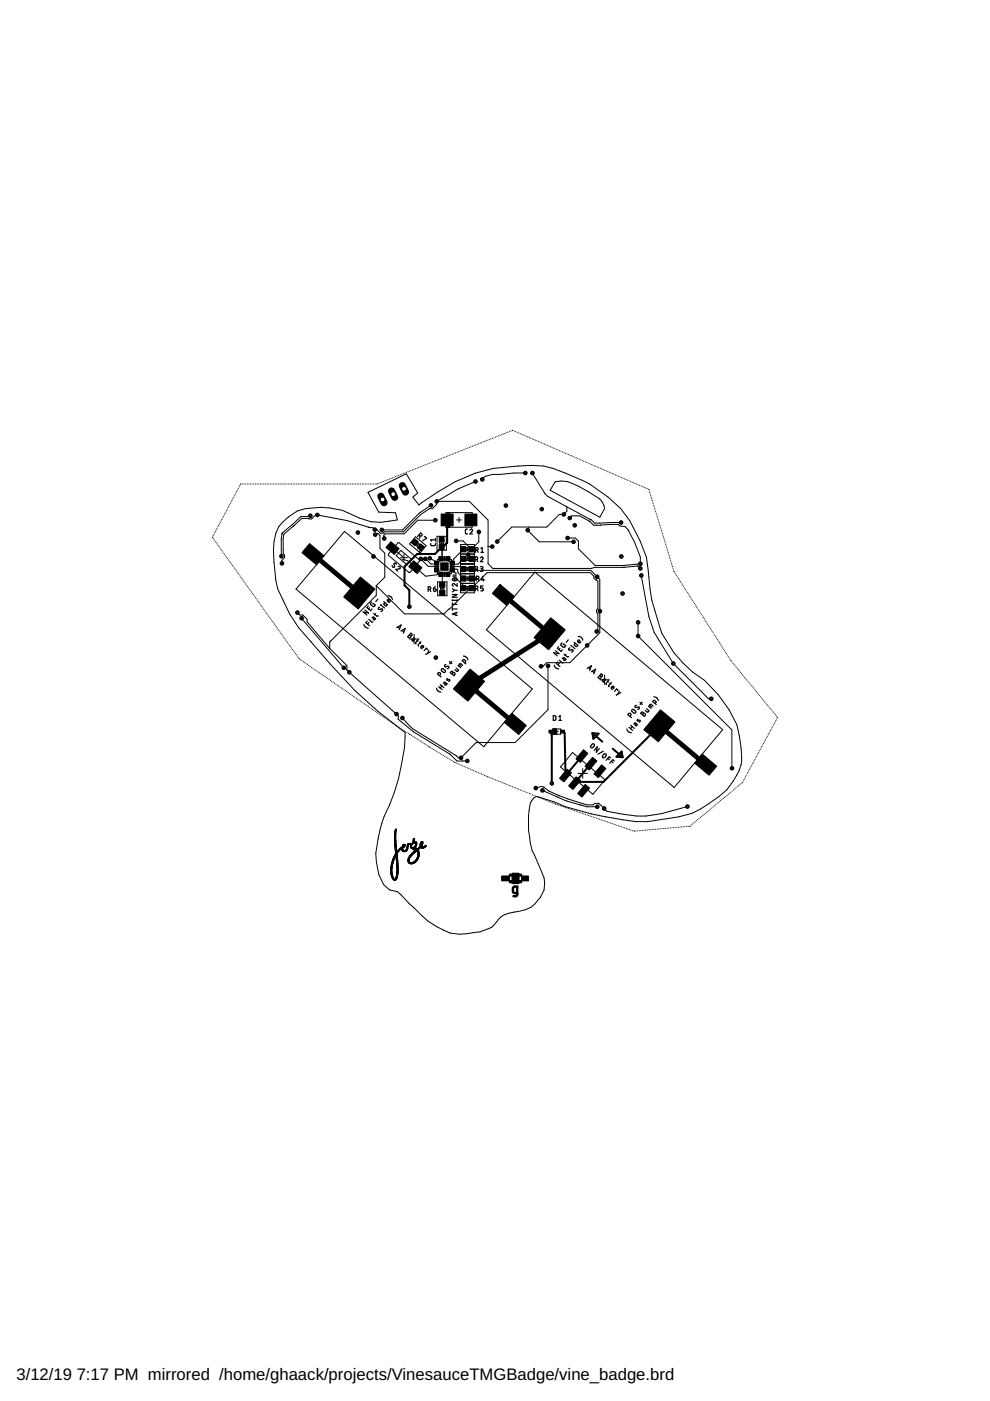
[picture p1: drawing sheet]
<svg xmlns="http://www.w3.org/2000/svg" width="210mm" height="297mm" viewBox="0 0 210 297" stroke-linecap="round" stroke-linejoin="round" font-family="sans-serif">
<defs><g id="words">
<g font-size="3.5">
<text x="3.5" y="292.5">3/12/19</text>
<text x="16.3" y="292.5">7:17 PM mirrored /home/ghaack/projects/VinesauceTMGBadge/vine_badge.brd</text>
</g>
</g></defs>
<g fill="#000" stroke="#000" stroke-width=".21">
<path d="M65.6 115.3l3.1 2.5-1.6 1.9-3.1-2.5zM82.9 114.9l1.7 1.4-1 1.3-1.8-1.5zM87.9 114.2l.8 .7-.7 .8-.8-.6zM89.2 115.3l.8 .7-.7 .8-.8-.6zM92.1 119.5h.9v.3h-.9zM92.1 120h.9v.3h-.9zM93.6 118h.3v.9h-.3zM93.1 115.5h1v1.1h-1zM93.1 113.8h1v1.1h-1zM94.1 118h.3v.9h-.3zM94.6 118h.3v.9h-.3zM93.5 119.3h1.5v1.6h-1.5z"/>
<path d="M93.5 109h2.6v2.5h-2.6zM95.4 120h1v.3h-1zM95.4 119.5h1v.3h-1zM97.7 115.9h1.1v1.1h-1.1zM97.7 117.9h1.1v1.1h-1.1zM99.4 115.9h1.1v1.1h-1.1zM99.4 117.9h1.1v1.1h-1.1zM98.6 109h2.5v2.5h-2.5zM76.4 122.3l3.1 2.6-3.6 4.2-3-2.5zM87.7 118.9l1.8 1.5-1.1 1.2-1.7-1.5zM92.1 120.5h.9v.3h-.9zM93.6 121.3h.3v.9h-.3z"/>
<path d="M93.2 123.5h1.1v1h-1.1zM93.2 125.2h1.1v1h-1.1zM94.1 121.3h.3v.9h-.3zM94.6 121.3h.3v.9h-.3zM95.4 120.5h1v.3h-1zM97.7 120.1h1.1v1.1h-1.1zM97.7 122.1h1.1v1.1h-1.1zM97.7 124.1h1.1v1.1h-1.1zM99.4 120.1h1.1v1.1h-1.1zM99.4 122.1h1.1v1.1h-1.1zM99.4 124.1h1.1v1.1h-1.1zM106 123.9l3.1 2.6-1.6 1.9-3.1-2.6z"/>
<path d="M116.8 131l3 2.5-3.5 4.3-3.1-2.6zM99.7 141.9l3 2.5-3.5 4.3-3.1-2.6zM108.5 151.2l3.1 2.6-1.6 1.9-3.1-2.5zM116.4 154.8h.8v.6h-.8zM118.9 154.8h.8v.6h-.8zM123.7 159l.9 .7-1.6 1.9-.9-.7zM140 150.5l3.1 2.6-3.5 4.2-3.1-2.6zM83.7 178.1h.2zM83.7 178h.2zM83.7 177.9l.2 .1zM83.7 177.9h.2zM83.7 177.8l.2 .1z"/>
<path d="M83.7 177.7l.2 .1zM83.7 177.7h.2zM83.7 177.6h.2zM83.7 177.5l.2 .1zM83.7 177.5h.2zM83.7 177.4l.2 .1zM83.7 177.4h.2zM83.7 177.3l.2 .1zM83.7 177.3h.2zM83.7 177.2l.2 .1zM83.7 177.2h.2zM83.7 177.1l.2 .1z"/>
<path d="M83.7 177.1h.2zM83.7 177l.2 .1zM83.7 177h.2zM83.7 176.9l.2 .1zM83.7 176.9h.2zM83.7 176.8h.2zM83.7 176.7h.2zM83.7 176.6l.2 .1zM83.7 176.6h.2zM83.7 179h.2zM83.7 178.9l.2 .1zM83.7 178.9h.2z"/>
<path d="M83.7 178.8l.2 .1zM83.7 178.8h.2zM83.7 178.7l.2 .1zM83.7 178.7h.2zM83.7 178.6h.2zM83.7 178.5h.2zM83.7 178.4l.2 .1zM83.7 178.4h.2zM83.7 178.3l.2 .1zM83.7 178.2l.2 .1zM83.7 178.2h.2zM83.7 177.8h.2z"/>
<path d="M83.7 176.8l.2 .1zM83.7 176.7l.2 .1zM83.7 176.5l.2 .1zM83.7 176.5h.2zM83.7 176.4l.2 .1zM83.7 176.4h.2zM83.7 176.3l.2 .1zM83.7 176.3h.2zM83.7 176.2l.2 .1zM83.7 176.2h.2zM83.7 176.1l.2 .1zM83.8 176.1h.1z"/>
<path d="M83.7 179.5h.3zM83.7 179.4l.3 .1zM83.7 179.4h.3zM83.7 179.3l.3 .1zM83.7 179.3h.3zM83.7 179.2l.3 .1zM83.7 179.2h.3zM83.7 179.1l.3 .1zM83.7 179.1h.3zM83.7 179h.3zM83.8 176l.2 .1zM83.8 176h.2z"/>
<path d="M83.8 179.9l.3 .1zM83.8 179.9h.3zM83.8 179.8l.3 .1zM83.8 179.8h.3zM83.8 179.7l.3 .1zM83.8 179.7h.3zM83.8 179.6l.3 .1zM83.8 179.6h.3zM83.8 179.5l.3 .1zM83.8 175.9l.3 .1zM83.8 175.9h.3zM83.9 175.8l.2 .1z"/>
<path d="M83.8 180h.3zM84.7 180h.3zM84.7 179.9l.3 .1zM84.8 179.9h.3zM84.8 179.8l.6 .1zM84.9 179.8h.5zM85.2 180h.2zM85.2 179.9l.2 .1zM85.2 179.9h.2zM85 179.7l.5 .1zM85.3 179.4l.2 .1zM85.3 179.4h.2z"/>
<path d="M85.3 179.3l.2 .1zM85.3 179.3h.2zM85 179.7h.6zM85.4 179.2l.2 .1zM85.4 179.2h.2zM85.1 179.6l.6 .1zM85.2 179.6h.5zM85.2 179.5l.6 .1zM85.3 179.5h.5zM85.6 179.4l.2 .1zM85.5 179h.3zM85.6 179.4h.3z"/>
<path d="M85.7 179.3l.2 .1zM85.7 179.3h.2zM85.4 179.1l.5 .1zM85.7 179.2l.2 .1zM85.5 179.1h.4zM85.7 179.2h.2zM86.2 180h.2zM86.2 179.9l.2 .1zM86.2 179.9h.3zM86.2 179.8l.3 .1zM86.3 179.8h.2zM86.3 179.7l.2 .1z"/>
<path d="M86.3 179.7h.2zM86.3 179.6l.2 .1zM86.3 179.6h.2zM86.3 179.5l.2 .1zM86.3 179.5h.3zM86.3 179.4l.3 .1zM86.3 179.4h.3zM86.3 179.3l.3 .1zM86.3 179.3h.3zM86.3 179.2l.3 .1zM86.3 179.2h.3zM86.4 179.1l.2 .1z"/>
<path d="M86.4 179.1h.4zM86.4 179h.5zM86.4 179h.6zM86.4 178.9l.6 .1zM86.6 178.9h.4zM86.8 178.8l.2 .1zM87 179.5h.2zM87.1 179.4h.1zM87.1 179.3l.1 .1zM87 179.6l.3 .1zM87 179.6h.3zM87 179.5l.3 .1z"/>
<path d="M87 179.4l.3 .1zM87.1 179.3h.2zM87.1 179.2l.2 .1zM87.1 179.2h.2zM87.1 179.7h.3zM87.1 179.1l.3 .1zM87.1 179.1h.3zM87.2 179h.2zM87.2 178.9l.3 .1zM87.3 178.9h.2zM87.4 178.8l.3 .1zM87.5 178.5h.3z"/>
<path d="M87.6 178.4l.2 .1zM87.5 178.4h.3zM87.6 178.3l.2 .1zM87.6 178.2l.2 .1zM87.6 178.1h.2zM87.4 178.8h.4zM87.6 178.2h.3zM87.6 178.1h.3zM87.6 178h.3zM87.6 177.9l.3 .1zM87.7 177.7l.2 .1zM87.4 178.7l.5 .1z"/>
<path d="M87.6 177.9h.3zM87.7 177.8l.2 .1zM87.7 177.8h.2zM87.1 179.8h.8zM87.1 179.7l.9 .1zM87.6 179.7h.5zM87.5 178.7h.6zM87.8 179.6h.3zM87.7 179.6l.4 .1zM87.9 179.5l.3 .1zM87.9 179.5h.3zM87.9 179.4l.3 .1z"/>
<path d="M87.9 179.4h.3zM87.9 178.5h.3zM88 179.3l.3 .1zM88 179.3h.3zM88.1 179.2l.2 .1zM88.1 179.2h.2zM88.1 179.1l.2 .1zM87.5 178.6h.8zM87.6 178.5h.7zM87.2 179.8l1.2 .1zM88.1 179.1h.3zM88.1 179h.3z"/>
<path d="M88.2 178.9l.2 .1zM88.2 178.9h.2zM88.2 178.8l.2 .1zM88.2 178.8h.2zM88.2 178.7l.2 .1zM88.2 178.7h.2zM87.2 179.9h1.2zM87.4 179.9l1.1 .1zM87.5 180h1.4zM88.6 179.9l.3 .1zM88.6 179.9h.4zM88.7 179.8l.3 .1z"/>
<path d="M88.8 179.8h.3zM88.8 179.7l.3 .1zM88.9 179.7h.3zM89 179.2l.3 .1zM89.1 179.2h.2zM89.1 179.1l.2 .1zM89.1 179.1h.2zM89.1 179h.2zM89.1 178.9l.2 .1zM89.1 178.9h.2zM89.1 178.8l.2 .1zM89.1 178.8h.2z"/>
<path d="M89.2 178.7l.1 .1zM89.1 179.4l.3 .1zM89.1 179.4h.3zM89.2 178.7h.2zM89.2 178.6h.2zM89 179.5h.4zM89.1 179.3l.3 .1zM89.1 179.3h.4zM89 179.5l.5 .1zM89.3 179.2l.2 .1zM89.4 179.2h.1zM89.4 179.1l.1 .1z"/>
<path d="M89.4 178.4l.2 .1zM89.4 179.1h.2zM89.4 179h.2zM89.3 178.5h.3zM89.5 179h.1zM89.5 178.9l.1 .1zM89.5 178.9h.1zM89.5 178.8h.2zM89.5 178.7l.2 .1zM89.5 178.7h.2zM89.5 178.6h.2zM89.3 178.5h.4z"/>
<path d="M89.4 179.8h.4zM89.3 179.7l.6 .1zM89.2 179.7h.8zM88.9 179.6l1.2 .1zM89 179.6h1.2zM89.7 179.5l.5 .1zM89.9 179.5h.4zM90 179.4h.3zM90.1 179.3l.2 .1zM90.1 179.3h.2zM89.9 179.4l.5 .1zM120.2 163.1l1 .8-1.6 1.9-1-.8z"/>
<path d="M122.2 164.7l.9 .8-1.6 1.9-.9-.8zM124.1 166.3l.9 .8-1.6 1.9-.9-.8zM125.6 160.6l1 .7-1.7 2-.9-.8zM127.6 162.2l.9 .7-1.6 2-1-.8zM148.9 159.9l3.1 2.6-1.7 1.9-3-2.6zM82.8 184.9l.3 .1zM82.8 184.8l.3 .1zM82.8 184.8h.3zM82.8 184.7h.3zM82.8 184.6h.3zM82.8 184.5h.3zM82.8 184.4l.3 .1z"/>
<path d="M82.8 184.4h.3zM82.8 184.3l.3 .1zM82.8 184.3h.3zM82.8 184.2l.3 .1zM82.8 185h.3zM82.8 184.7l.3 .1zM82.8 184.2h.3zM82.8 184.1l.3 .1zM82.8 184.1h.3zM82.8 183.9l.3 .1zM82.9 185.4h.2zM82.9 185.3h.2z"/>
<path d="M82.9 185.2l.2 .1zM82.9 185.2h.2zM82.9 185.1h.2zM82.9 185h.2zM82.9 184l.2 .1zM82.9 184h.2zM82.9 183.9h.2zM82.9 183.8l.2 .1zM82.9 183.8h.2zM82.9 183.7l.2 .1zM82.9 183.7h.2zM82.9 185.5h.3z"/>
<path d="M82.9 185.4l.3 .1zM82.9 185.3l.3 .1zM82.9 183.6l.3 .1zM82.9 183.6h.3zM82.9 183.5l.3 .1zM82.9 183.5h.3zM82.9 183.4l.3 .1zM83 185.7h.2zM82.9 185.6l.3 .1zM82.9 185.6h.3zM82.9 183.4h.3zM83 183.3l.2 .1z"/>
<path d="M83 183.3h.2zM83 183.2l.2 .1zM83 185.8l.3 .1zM83 185.8h.3zM83 185.7l.3 .1zM83 183.2h.3zM83 183.1l.3 .1zM83 183.1h.3zM83 183l.3 .1zM83.1 186h.2zM83.1 185.9l.2 .1zM83 185.9h.3z"/>
<path d="M83 183h.3zM83.1 182.9l.2 .1zM83.1 182.9h.2zM83.1 182.8l.2 .1zM83.1 186l.3 .1zM83.1 182.8h.3zM83.1 182.7l.3 .1zM83.1 182.7h.3zM83.1 182.6l.3 .1zM83.2 186.2h.2zM83.1 186.1l.3 .1zM83.1 186.1h.3z"/>
<path d="M83.1 182.6h.3zM83.2 182.5l.2 .1zM83.2 186.2l.3 .1zM83.2 182.5h.3zM83.2 182.4l.3 .1zM83.2 182.4h.3zM83.2 186.3h.3zM83.2 182.3l.3 .1zM83.2 182.3h.3zM83.3 182.2l.2 .1zM83.3 186.3l.3 .1zM83.3 182.2h.3z"/>
<path d="M83.3 182.1l.3 .1zM83.3 182.1h.3zM83.3 186.4h.3zM83.3 182l.3 .1zM83.4 182h.3zM83.4 181.9h.3zM83.4 181.8h.3zM83.5 181.8h.2zM83.5 181.7l.3 .1zM83.5 181.7h.3zM83.5 181.6l.3 .1zM83.6 181.5l.2 .1z"/>
<path d="M83.6 181.5h.2zM83.6 181.5h.3zM83.5 186.6h.4zM83.4 186.5l.5 .1zM83.4 186.5h.7zM83.3 186.4l.8 .1zM83.8 186.4h.3zM83.8 186.3l.3 .1zM83.8 180.4l.3 .1zM83.8 180.4h.3zM83.8 180.3l.3 .1zM83.8 180.3h.3z"/>
<path d="M83.8 180.2l.3 .1zM83.8 180.2h.3zM83.8 180.1l.3 .1zM83.8 180.1h.3zM83.8 180l.3 .1zM83.8 186.3h.3zM83.8 180.5h.3zM83.9 186.2l.3 .1zM83.9 186.2h.3zM83.9 186.1l.3 .1zM83.9 186.1h.3zM83.9 186l.3 .1z"/>
<path d="M83.9 181.5h.3zM83.7 181.4h.5zM83.7 181.3h.5zM83.7 181.2l.5 .1zM83.8 181.1l.4 .1zM83.8 181.1h.4zM83.9 181l.3 .1zM83.9 181h.3zM84 186h.2zM84 185.9l.2 .1zM84 185.9h.2zM84 181.9h.2z"/>
<path d="M84 181.8h.2zM84 181.7l.2 .1zM83.9 181.7h.3zM83.9 181.6l.3 .1zM83.9 181.5l.3 .1zM83.9 180.9h.3zM83.9 180.8l.3 .1zM84 185.8l.3 .1zM84 185.8h.3zM84.1 185.7l.2 .1zM84.1 185.7h.2zM84.1 185.6l.2 .1z"/>
<path d="M84.1 185.6h.2zM84.1 182.4h.2zM84.1 182.3l.2 .1zM84.1 182.3h.2zM84 182.2l.3 .1zM84 182.2h.3zM84 182.1l.3 .1zM84 182.1h.3zM84 182l.3 .1zM84 182h.3zM84 181.8h.3zM83.9 180.8h.4z"/>
<path d="M84.1 185.5h.2zM84.1 185.4l.2 .1zM84.1 185.4h.2zM84.1 185.3l.2 .1zM84.1 185.3h.2zM84.1 185.2l.2 .1zM84.1 185.2h.2zM84.1 183.1l.2 .1zM84.1 182.9l.2 .1zM84.1 182.9h.2zM84.1 182.8l.2 .1zM84.1 182.8h.2z"/>
<path d="M84.1 182.7l.2 .1zM84.1 182.7h.2zM84.1 182.6l.2 .1zM84.1 182.6h.2zM84.1 182.5l.2 .1zM84.1 182.5h.2zM84.1 182.4l.2 .1zM83.8 180.7l.5 .1zM84.1 185.1h.3zM84.1 185h.3zM84.1 184.8h.3zM84.1 183.7h.3z"/>
<path d="M84.1 183.6h.3zM84.1 183.5l.3 .1zM84.1 183.5h.3zM84.1 183.4l.3 .1zM84.1 183.4h.3zM84.1 183.3l.3 .1zM84.1 183.3h.3zM84.1 183.2l.3 .1zM84.1 183.2h.3zM84.1 183.1h.3zM84.1 183l.3 .1zM84.1 183h.3z"/>
<path d="M83.8 180.7h.6zM83.8 180.6l.6 .1zM84.2 185.1h.2zM84.2 184.9l.2 .1zM84.2 184.8l.2 .1zM84.2 184.7l.2 .1zM84.2 184.7h.2zM84.2 184.6h.2zM84.2 184.5h.2zM84.2 184.4l.2 .1zM84.2 184.4h.2zM84.2 184.3l.2 .1z"/>
<path d="M84.2 184.3h.2zM84.2 184.2l.2 .1zM84.2 184.2h.2zM84.2 184.1l.2 .1zM84.2 184.1h.2zM84.2 184l.2 .1zM84.2 184h.2zM84.2 183.9l.2 .1zM84.2 183.9h.2zM84.2 183.8l.2 .1zM84.2 183.8h.2zM84.2 183.7l.2 .1z"/>
<path d="M84.2 183.6l.2 .1zM83.9 180.6h.6zM83.8 180.5l.7 .1zM84.2 180.5h.3zM84.3 180.4l.3 .1zM84.3 180.4h.3zM84.3 180.3l.3 .1zM84.4 180.3h.3zM84.4 180.2l.4 .1zM84.5 180.2h.3zM84.5 180.1l.4 .1zM84.6 180.1h.3z"/>
<path d="M84.6 180l.4 .1zM85.2 180.2h.2zM85.2 180.1l.2 .1zM85.2 180.1h.2zM85.2 180l.2 .1zM85.2 180.2l.3 .1zM85.2 180.3h.4zM85.5 180.5l.4 .1zM85.4 180.5h.7zM85.3 180.4l.8 .1zM85.3 180.4h.9zM85.3 180.3l.9 .1z"/>
<path d="M85.9 180.3h.4zM86 180.2l.3 .1zM86 180.2h.4zM86.1 180.1l.3 .1zM86.1 180.1h.3zM86.2 180l.2 .1zM86.5 182.5l.2 .1zM86.5 182.5h.2zM86.5 182.4l.2 .1zM86.5 182.4h.2zM86.5 182.3l.2 .1zM86.5 182.3h.2z"/>
<path d="M86.5 182.2l.2 .1zM86.5 182.7h.3zM86.5 182.6l.3 .1zM86.5 182.6h.3zM86.5 182.2h.3zM86.5 182.1l.3 .1zM86.5 182.1h.3zM86.5 182.7l.3 .1zM86.5 182l.3 .1zM86.5 182h.3zM86.6 182.8h.3zM86.6 181.9h.3z"/>
<path d="M86.6 181.8h.3zM86.6 181.8h.4zM86.6 182.8l.4 .1zM86.7 181.7l.3 .1zM86.7 181.7h.3zM86.7 181.6l.4 .1zM86.8 181.5l.3 .1zM86.8 181.5h.3zM86.8 181.5h.4zM86.9 181.4h.3zM86.9 181.4h.4zM86.9 181.3h.5z"/>
<path d="M87.1 183.1l.3 .1zM87 181.3h.4zM87.1 181.2l.3 .1zM87.1 181.1l.3 .1zM87.2 181l.3 .1zM86.9 183.1h.7zM87.1 181.1h.5zM87.2 181h.5zM86.8 183l.9 .1zM87.3 181h.4zM87.3 180.9h.5zM86.7 183h1.1z"/>
<path d="M87.4 180.8l.4 .1zM87.4 180.8h.5zM86.6 182.9l1.3 .1zM87.5 180.7l.4 .1zM87.7 180.1l.2 .1zM86.6 182.9h1.4zM87.5 182.8l.5 .1zM87.5 180.7h.5zM87.6 180.6l.4 .1zM87.7 180.1h.4zM87.6 182.8h.5zM87.7 180.6h.4z"/>
<path d="M87.7 182.7l.5 .1zM87.7 180.5l.5 .1zM87.8 182.7h.4zM87.8 180.5h.4zM87.8 182.6l.5 .1zM87.8 180.4l.5 .1zM87.9 182.6h.4zM88 182.5h.3zM87.9 182.5l.5 .1zM87.9 180.4h.5zM88.1 182.4l.3 .1zM88.1 182.4h.4z"/>
<path d="M88.2 182.3l.3 .1zM88.2 182.3h.3zM88.2 182.2l.4 .1zM88.3 182.2h.3zM88.3 182.1l.3 .1zM88.3 182.1h.4zM88.4 182l.3 .1zM88.4 182h.3zM88.2 180.2h.5zM88.2 180.1l.5 .1zM88.4 181.9h.3zM87.9 180.3l.8 .1z"/>
<path d="M88.2 180.2l.5 .1zM88.2 180.1h.5zM88.1 180.3h.6zM88.5 181.8h.3zM88.5 181.7l.3 .1zM88.5 180.4l.3 .1zM88.5 180.4h.3zM87.6 180l1.2 .1zM88.5 181.7h.3zM88.6 181.6l.2 .1zM88.6 181.5l.2 .1zM88.6 180.6l.2 .1z"/>
<path d="M88.5 180.6h.3zM88.5 180.5l.3 .1zM88.5 180.5h.3zM88.6 181.5h.3zM88.6 181.4h.3zM88.6 180.8h.3zM88.6 180.7l.3 .1zM88.6 180.7h.3zM88.6 181.3h.3zM88.6 181.2l.3 .1zM88.6 181.1l.3 .1zM88.6 181.1h.3z"/>
<path d="M88.6 181l.3 .1zM88.6 181h.3zM88.6 180.9h.3zM88.6 180.8l.3 .1zM106.4 186.7l1.6 .1zM106.4 186.6h1.6zM106.4 186.5h1.6zM106.4 186.4h1.6zM106.4 186.2l1.6 .1zM106.4 186.2h1.6zM106.4 186.1h1.6zM106.4 185.9l1.6 .1z"/>
<path d="M106.4 185.8l1.6 .1zM106.4 185.7l1.6 .1zM108.6 187.3h1.4zM108.6 187.2l1.4 .1zM108.6 186.7l1.4 .1zM108.6 186.6h1.4zM108.6 186.5h1.4zM108.6 186.4h1.4zM108.6 186.2l1.4 .1zM108.6 186.2h1.4zM108.6 186.1h1.4zM108.6 185.9l1.4 .1z"/>
<path d="M108.6 185.8l1.4 .1zM108.6 185.7l1.4 .1zM108.6 185.2l1.4 .1zM108.6 185.1l1.4 .1zM108 187.1l2.6 .1zM108 187h2.6zM108 186.9h2.6zM108 186.8h2.6zM108 185.7h2.6zM108 185.5l2.6 .1zM108 185.4l2.6 .1zM108 185.3l2.6 .1z"/>
<path d="M110.6 186.7l1.5 .1zM110.6 186.6h1.5zM110.6 186.5h1.5zM110.6 186.4h1.5zM110.6 186.2l1.5 .1zM110.6 186.2h1.5zM110.6 186.1h1.5zM110.6 185.9l1.5 .1zM110.6 185.8l1.5 .1zM110.6 185.7l1.5 .1z"/>
</g>
<path d="M109.7 189.3h-.7l-.2-.2v-.9l.2-.2h.7v1.7l-.2 .3h-.6" fill="none" stroke="#000" stroke-width=".51"/>
<g fill="none" stroke="#000" stroke-width=".21">
<path d="M86.8 99.9h.1M87.1 99.8h.1M87.5 99.6l-.1 .1M87.8 99.5h.1M88.1 99.4h.1M88.4 99.3h.1M88.8 99.1h-.1M89.1 99h.1M89.4 98.8v.1M89.8 98.7h-.1M90.1 98.6h-.1M90.4 98.5h.1"/>
<path d="M90.7 98.3v.1M91.1 98.2h-.1M91.4 98.1h.1M91.7 98h.1M92 97.8h.1M92.4 97.7h-.1M92.7 97.6h-.1M93 97.4v.1M93.3 97.3h.1M93.7 97.2h-.1M94 97v.1M94.3 96.9h.1"/>
<path d="M94.6 96.8h.1M94.9 96.7h.1M95.2 96.5h.1M95.6 96.4h.1M95.9 96.3h.1M96.3 96.1l-.1 .1M96.6 96h.1M96.9 95.9h.1M97.3 95.8h-.1M97.6 95.6l-.1 .1M97.9 95.5h.1M98.2 95.4h.1"/>
<path d="M98.5 95.2h.1M98.9 95.1h-.1M99.2 95h.1M99.5 94.8v.1M99.9 94.7h-.1M100.2 94.6h.1M100.5 94.5h.1M100.8 94.3v.1M101.2 94.2h-.1M101.5 94.1h.1M101.8 94h.1M102.2 93.8h-.1"/>
<path d="M102.5 93.7h-.1M102.8 93.6h.1M103.1 93.4v.1M103.5 93.3h-.1M103.8 93.2h-.1M104.1 93v.1M104.4 92.9h.1M104.7 92.8h.1M105.1 92.7h.1M105.4 92.5h.1M105.7 92.4h.1M106.1 92.3h-.1"/>
<path d="M106.4 92.1l-.1 .1M106.7 92h.1M107 91.9h.1M107.4 91.8h-.1M107.7 91.6v.1M108 91.5h.1M108.3 91.4h.1M108.6 91.2h.1M109 91.4h.1M109.3 91.5h.1M109.6 91.7h.1M110 91.8h.1"/>
<path d="M110.3 91.9h.1M110.6 92.1h.1M110.9 92.2h.1M111.2 92.4h.1M111.5 92.5h.1M111.9 92.6h.1M112.2 92.8h.1M112.5 92.9h.1M112.8 93l.1 .1M113.2 93.2h.1M113.5 93.3h.1M113.8 93.5h.1"/>
<path d="M114.1 93.6h.1M114.4 93.7h.1M114.8 93.9h.1M115.1 94h.1M115.4 94.1v.1M115.7 94.3h.1M116.1 94.4h.1M116.4 94.6h.1M116.7 94.7h.1M117 94.8l.1 .1M117.3 95h.1M117.6 95.1h.1"/>
<path d="M118 95.3h.1M118.3 95.4h.1M118.6 95.5l.1 .1M118.9 95.7h.1M119.3 95.8h.1M119.6 96h.1M119.9 96.1h.1M120.2 96.2v.1M120.5 96.4h.1M120.9 96.5h.1M121.2 96.6v.1M121.5 96.8h.1"/>
<path d="M121.8 96.9h.1M122.1 97.1h.1M122.4 97.2h.1M122.8 97.3v.1M123.1 97.5h.1M123.4 97.6h.1M123.7 97.8h.1M124.1 97.9h.1M124.4 98v.1M124.7 98.2h.1M125 98.3h.1M125.3 98.5h.1"/>
<path d="M125.7 98.6h.1M126 98.7v.1M126.3 98.9h.1M126.6 99h.1M127 99.2h.1M127.3 99.3h.1M127.6 99.4h.1M127.9 99.6h.1M128.2 99.7h.1M128.5 99.8l.1 .1M128.9 100h.1M45 113.9h.1"/>
<path d="M45.2 113.6h.1M45.2 114.2h.1M45.4 113.2v.1M45.4 114.5h.1M45.6 112.9l-.1 .1M45.6 114.8h.1M45.7 112.6v.1M45.8 115v.1M45.9 112.3l-.1 .1M46 115.3l.1 .1M46 112h.1M46.2 111.7h.1"/>
<path d="M46.2 115.6h.1M46.4 111.4h.1M46.4 115.9h.1M46.5 111.1h.1M46.6 116.2h.1M46.7 110.7v.1M46.8 116.5h.1M46.9 110.4l-.1 .1M47 110.1v.1M47.1 116.7v.1M47.2 109.8v.1M47.2 117l.1 .1"/>
<path d="M47.4 109.5h-.1M47.5 117.3h.1M47.5 109.2h.1M47.6 117.6h.1M47.7 108.9h.1M47.9 117.9h.1M47.9 108.6h.1M48 118.2h.1M48 108.2v.1M48.2 107.9v.1M48.3 118.4v.1M48.4 107.6l-.1 .1"/>
<path d="M48.5 118.7h.1M48.5 107.3v.1M48.7 119h.1M48.7 107h.1M48.9 119.3h.1M48.9 106.7h.1M49 106.4h.1M49.1 119.6h.1M49.2 106v.1M49.3 119.8v.1M49.4 105.7l-.1 .1M49.5 105.4v.1"/>
<path d="M49.7 105.1v.1M49.9 104.8h-.1M50 104.5h.1M50.2 104.2h.1M50.4 103.9h-.1M50.5 103.5v.1M50.7 103.2v.1M50.9 102.9l-.1 .1M51.1 102.6l-.1 .1M51.4 102.6h.1M51.7 102.6h.1M52.1 102.6h.1"/>
<path d="M52.4 102.6h.1M52.8 102.6h.1M53.1 102.6h.1M53.5 102.6h.1M53.8 102.6h.1M54.2 102.6h.1M54.5 102.6h.1M54.9 102.6h.1M55.2 102.6h.1M55.5 102.6h.1M55.9 102.6h.1M56.2 102.6h.1"/>
<path d="M56.6 102.6h.1M56.9 102.6h.1M57.3 102.6h.1M57.6 102.6h.1M58 102.6h.1M58.3 102.6h.1M58.7 102.6h.1M59 102.6h.1M59.4 102.6h.1M59.7 102.6h.1M59.8 113.1h.1M60.1 102.6h.1"/>
<path d="M60.4 102.6h.1M60.8 102.6h.1M61.1 102.6h.1M61.5 102.6h.1M61.8 102.6h.1M62.2 102.6h.1M62.2 111.6l1.8-1.7 2.1 .1 .8-.8a45.9 45.9 0 0 1 11.2 2.6M62.2 111.6l-2 1.7-.2 1v3.1l.3 .3v.5l-.5 .6v.6M62.2 111.6h.1M62.5 102.6h.1M62.8 102.6h.1M63.2 102.6h.1"/>
<path d="M63.5 102.6h.1M63.9 102.6h.1M64.2 102.6h.1M64.6 102.6h.1M64.9 102.6h.1M65.3 102.6h.1M65.6 102.6h.1M65.8 109.3l-.2 .2h-1.8l-4 3.6-.2 1.2v3.6M66 102.6h.1M66.3 102.6h.1M66.7 102.6h.1M67 102.6h.1"/>
<path d="M67.4 102.6h.1M67.7 102.6h.1M68.1 102.6h.1M68.4 102.6h.1M68.8 102.6h.1M69.1 102.6h.1M69.5 102.6h.1M69.8 102.6h.1M70.1 102.6h.1M70.5 102.6h.1M70.8 102.6h.1M71.2 102.6h.1"/>
<path d="M71.5 102.6h.1M71.9 102.6h.1M72.2 102.6h.1M72.6 102.6h.1M72.9 102.6h.1M73.3 102.6h.1M73.6 102.6h.1M74 102.6h.1M74.3 102.6h.1M74.7 102.6h.1M75 102.6h.1M75.4 102.6h.1"/>
<path d="M75.7 102.6h.1M76.1 102.6h.1M76.4 102.6h.1M76.8 102.6h.1M77.1 102.6h.1M77.4 102.6h.1M77.8 102.6h.1M78.1 111.8h.1M78.1 102.6h.1M78.5 102.6h.1M78.8 102.6h.1M79.2 102.6h.1"/>
<path d="M79.5 102.6h.1M79.5 113.3l.3-.2h.4l.4 .4v2.7l1 1.1v5.1l-1.8 1.8M80 102.6h-.1M80.3 102.5h.1M80.6 102.3v.1M81 102.2h-.1M81.3 102.1h-.1M81.6 102h.1M81.9 101.8h.1M82.3 101.7h-.1M82.6 101.6h-.1M82.9 101.4v.1"/>
<path d="M83.2 101.3h.1M83.6 101.2h-.1M83.9 101l-.1 .1M84.2 100.9h.1M84.5 100.8h.1M84.8 100.7h.1M85.2 100.5h.1M85.5 100.4h.1M85.9 100.3h-.1M86.2 100.1l-.1 .1M86.5 100h.1M89.2 118.5l1.6 1.6h1.8"/>
<path d="M89.2 116.1l-.4 1.4M90.1 118.5l1.3 1.1h1.2M91.1 107.8l-1.9 1.3-3.7 3.7h-4l-.3 .3h-.6l-.7-.8h-.5l-.4-.4-.9-.1M91.1 107.8v.1M91.1 118.4l1.5 .7M91.4 107.1l-2.5 1.7-3.6 3.6h-4.4M92.1 119h.8l.1 .2h-.9zM92.1 119.2h.9M92.1 119.1h.9M92.1 119h.8M92.3 110.3h-3.7l-2.9 2.9h-4l-.3 .3v.7M92.6 106.3v.6l-.9 .9h-.6"/>
<path d="M92.6 119.1h.1M92.6 106.3h6.9l4 4v9.2l1 1h20.8l.9-.2h6.2M93.1 118.8l.2 .1M93.1 118.8v-.8h.2l-.1 .9M93.1 118.7h.2M93.1 118.6h.2M93.1 118.5h.2M93.1 118.4h.2M93.1 118.3h.2M93.1 118.2h.2M93.1 118.1h.2M93.2 118.8h.1"/>
<path d="M93.2 118.5h.1M94.8 115.1l-1.1 1M95.1 118.8h.2M95.1 118.7h.2M95.1 118.6h.2M95.1 118.5h.2M95.1 118.4h.2M95.1 118.3h.2M95.1 118.2h.2M95.1 118.1h.2M95.2 118.5h.1M95.3 118.8v-.8h-.2v.9h.1"/>
<path d="M95.3 118.8l-.1 .1M95.4 119.2h.9M95.5 119.1h.8M95.6 119h.7M95.6 119h.7v.2h-.9zM95.9 119.1h.1M98.3 118.5l-1.2 1.1h-1.2M98.3 116.5l-2 1.9-.4 .7M98.7 118.5h.7M98.7 116.5h.8M99.2 117.6v.2l.7 .7M100.8 102.1l-3.7 1.6-4.5 2.6"/>
<path d="M101.5 112.8v2.1l-1.6 1.6-1.7-1.8h-1.5M103.5 115.9h.9M111.4 100.3l-7 .3-1.5 .4-.7 .6M111.9 112.4l2.4 2.5h7.3M112.1 111.7l.1 .1M112.9 100.3l2.6 4.4 .6 .5 3.9 2.2M120 107.4l5.4 2.8 .7 .7 5.6-.1M120 107.4l.2 .1v.9l-.7 .7h-.9l-2.7 2.7-7.4-.1-3.1 3.1M120.8 109.8l.4-.4h1.7l2 1M124.9 110.4l1 1 5.2-.2 .3 .3 1.1 .2 .7 .6 1.4 2.7 1.2 3.1v1.4l-3.6 .4h-6l-3.6-3.5v-1.7l-.6-.6h-1.7M124.9 110.4v.1M125.1 110.6h.1"/>
<path d="M125.3 110.2h.1M129.2 100.1h.1M129.5 100.3h.1M129.8 100.4h.1M130.2 100.5v.1M130.5 100.7h.1M130.8 100.8h.1M131.1 101h.1M131.4 101.1h.1M131.8 101.2v.1M132.1 101.4h.1M132.4 101.5h.1"/>
<path d="M132.7 101.7h.1M133 101.8h.1M133.4 101.9v.1M133.7 102.1h.1M134 102.2h.1M134.3 102.3l.1 .1M134.6 102.5h.1M135 102.6h.1M135.3 102.8h.1M135.6 102.9h.1M135.9 103l.1 .1M136.2 103.2h.1"/>
<path d="M136.6 103.3h.1M136.9 103.5h.1M137.2 103.6h.1M137.5 103.7l.1 .1M137.7 104.1h.1M137.8 104.4v.1M137.9 104.8h.1M138 105.1h.1M138.1 105.4v.1M138.2 105.7v.1M138.3 106.1h.1M138.4 106.4v.1"/>
<path d="M138.5 106.8h.1M138.6 107.1h.1M138.7 107.4v.1M138.8 107.8h.1M138.9 108.1h.1M139 108.4v.1M139.1 108.8h.1M139.2 109.1h.1M139.3 109.4v.1M139.4 109.8h.1M139.5 110.1h.1M139.6 110.4v.1"/>
<path d="M139.7 110.8h.1M139.8 111.1h.1M139.9 111.4v.1M140 111.8h.1M140.1 112.1h.1M140.2 112.4l.1 .1M140.3 112.8h.1M140.4 113.1h.1M140.5 113.4v.1M140.6 113.8h.1M140.7 114.1l.1 .1M140.8 114.4l.1 .1"/>
<path d="M140.9 114.8h.1M141.1 115.1h.1M141.2 115.4v.1M141.2 115.8h.1M141.4 116.1h.1M141.5 116.4v.1M141.6 116.8h.1M141.7 117.1h.1M141.8 117.4v.1M141.9 117.8h.1M142 118.1v.1M142.1 118.4v.1"/>
<path d="M142.2 118.8h.1M142.3 119.1h.1M142.4 119.4v.1M142.5 119.8h.1M49.5 120.1v.1M49.7 120.4v.1M49.9 120.7h.1M50.1 121h.1M50.3 121.3h.1M50.5 121.5v.1M50.7 121.8v.1M50.9 122.1v.1"/>
<path d="M51.1 122.4h.1M51.3 122.7h.1M51.5 123h.1M51.7 123.3h.1M51.9 123.5v.1M52.1 123.8h.1M52.3 124.1h.1M52.5 124.4h.1M52.7 124.7h.1M52.9 124.9v.1M53.1 125.2v.1M53.3 125.5h.1"/>
<path d="M53.5 125.8h.1M53.7 126.1h.1M53.9 126.4h.1M54.1 126.6v.1M54.3 126.9v.1M54.5 127.2h.1M54.7 127.5h.1M54.9 127.8h.1M55.1 128.1h.1M55.3 128.3l.1 .1M55.5 128.6l.1 .1M55.7 128.9h.1"/>
<path d="M55.9 129.2h.1M56.1 129.5h.1M56.3 129.8h.1M56.5 130l.1 .1M56.7 130.3h.1M56.9 130.6h.1M57.1 130.9h.1M57.3 131.2h.1M57.6 131.4v.1M57.7 131.7l.1 .1M58 132h.1M58.1 132.3h.1"/>
<path d="M58.4 132.6h.1M58.5 132.9h.1M58.8 133.1v.1M59 133.4v.1M59.2 133.7v.1M59.4 134h.1M59.6 134.3h.1M59.8 134.6h.1M60 134.8v.1M60.2 135.1h.1M60.4 135.4h.1M60.6 135.7h.1"/>
<path d="M60.8 136h.1M61 136.2v.1M61.2 136.5v.1M61.4 136.8v.1M61.6 137.1h.1M61.8 137.4h.1M62 137.7h.1M62.2 137.9v.1M62.4 138.2v.1M62.6 138.5v.1M62.8 138.8h.1M63 139.1h.1"/>
<path d="M63 129.9l.5 .5h.7l.9 .9v.5l4.7 5.6 3.8 3.7-.1 .9 10.6 9.4 .4 .5-.1 .6 3.3 2.7 7.7 4.7M63.2 139.4h.1M63.4 139.7h.1M63.7 139.9h.1M63.9 131.1l9 10.5M70.1 135.9h.1M70.1 135.9l-.2 .2v1.4M79.8 124.2l6 6h8.3l9.2-8.8h21.9l.7 .8v.4l.9 .6v5.8l-.3 .3v.6l.3 .3v3.4l-.3 .3M79.8 124.2v2l-9.7 9.7M88.1 120.2l2.1 2 3.1-.4M92.1 121l.9 .1-.1 .1h-.8zM92.1 121.2h.8"/>
<path d="M92.1 121.1h.9M92.6 121.1h.1M93 121.1h-.9M93.1 122.2h.2M93.1 122.1h.2M93.1 122h.2M93.1 121.9h.2M93.1 121.8h.2M93.1 121.7h.2M93.1 121.6h.2M93.1 121.5h.2M93.2 121.4h.1"/>
<path d="M93.3 121.3v.9h-.2v-.7M93.3 121.3l-.2 .2M93.7 121.8l.1 2.2M95.1 122.2h.2M95.1 122.1h.2M95.1 122h.2M95.1 121.9h.2M95.1 121.8h.2M95.1 121.7h.2M95.1 121.6h.2M95.1 121.5h.2M95.1 121.4h.2"/>
<path d="M95.2 121.3l.1 .2M95.2 121.3l-.1 .9h.2v-.7M95.2 121.8h.1M95.4 121h.9v.2h-.7zM95.4 121.1h.9M95.5 121.1h.8M95.5 121.2h.8M95.9 121.1h.1M95.9 121.1l.8 .4v1.1l1.6 1.5v.6M95.9 120.6l1 .1 .2 .1v.6l1.2 1.3M95.9 120.1h1.8l.6 .5M98.7 120.6h.8"/>
<path d="M98.7 122.7h.8M98.7 124.7h.8M99.9 120.6l.5 .3h24.9l1.9 2v11.3l-6.4 6.3h-4.9l-.8 .8h-.4M99.9 122.7h.6M132.4 120.3l2.9-.3 .4 .5M132.4 120.3h.1M135.3 132v2.9l19.9 19.8v8.2M136 122l1.6 8.7 1.1 3.4 4 6.6 7.5 7.4h.6M142.6 120.1h.1M142.7 120.4v.1M142.8 120.8h.1M142.9 121.2h.1"/>
<path d="M142.9 121.1v.1M143.1 121.4v.1M143.3 121.7v.1M143.5 122v.1M143.7 122.3v.1M143.8 122.6l.1 .1M144 122.9l.1 .1M144.2 123.2l.1 .1M144.4 123.5h.1M144.6 123.8h.1M144.8 124.1h.1M145 124.4h.1"/>
<path d="M145.2 124.7h.1M145.4 125h.1M145.5 125.3h.1M145.7 125.6h.1M145.9 125.9h.1M146.1 126.2h.1M146.3 126.4v.1M146.5 126.7v.1M146.7 127v.1M146.9 127.3v.1M147 127.6l.1 .1M147.2 127.9l.1 .1"/>
<path d="M147.4 128.2v.1M147.6 128.5v.1M147.8 128.8v.1M148 129.1v.1M148.2 129.4v.1M148.4 129.7h.1M148.5 130h.1M148.7 130.3h.1M148.9 130.6h.1M149.1 130.9h.1M149.3 131.2h.1M149.5 131.5h.1"/>
<path d="M149.7 131.8h.1M149.9 132.1h.1M150.1 132.4h.1M150.2 132.7h.1M150.4 132.9l.1 .1M150.6 133.2v.1M150.8 133.5v.1M151 133.8v.1M151.2 134.1v.1M151.4 134.4v.1M151.6 134.7h.1M151.7 135h.1"/>
<path d="M151.9 135.3h.1M152.1 135.6h.1M152.3 135.9h.1M152.5 136.2h.1M152.7 136.5h.1M152.9 136.8h.1M153.1 137.1h.1M153.2 137.4h.1M153.4 137.7h.1M153.6 138h.1M153.8 138.3h.1M154 138.6h.1"/>
<path d="M154.2 138.9h.1M154.4 139.1v.1M154.6 139.4v.1M154.7 139.7l.1 .1M64 140.1h.1M64.3 140.3h.1M64.6 140.5h.1M64.9 140.7h.1M65.2 140.9h.1M65.4 141.1h.1M65.7 141.3h.1M66 141.5h.1"/>
<path d="M66.3 141.7h.1M66.6 141.9h.1M66.9 142.1h.1M67.2 142.3h.1M67.5 142.5h.1M67.8 142.7h.1M68 142.9h.1M68.3 143.1h.1M68.6 143.3h.1M68.9 143.4v.1M69.2 143.7h.1M69.5 143.8v.1"/>
<path d="M69.8 144.1h.1M70 144.3h.1M70.3 144.4l.1 .1M70.6 144.7h.1M70.9 144.8l.1 .1M71.2 145.1h.1M71.5 145.2v.1M71.8 145.4v.1M72.1 145.6v.1M72.3 145.8l.1 .1M72.6 146l.1 .1M72.9 146.2l.1 .1"/>
<path d="M73.2 146.4l.1 .1M73.5 146.6v.1M73.8 146.8v.1M74.1 147v.1M74.4 147.2v.1M74.7 147.4h.1M74.9 147.6l.1 .1M75.2 147.8h.1M75.5 148v.1M75.8 148.2v.1M76.1 148.4h.1M76.4 148.6v.1"/>
<path d="M76.7 148.8h.1M77 149h.1M77.2 149.2h.1M77.5 149.4h.1M77.8 149.6h.1M78.1 149.8h.1M78.4 150h.1M78.7 150.2h.1M79 150.4h.1M79.2 150.6h.1M79.5 150.8h.1M79.8 151h.1"/>
<path d="M80.1 151.2h.1M80.4 151.4h.1M80.7 151.6h.1M81 151.8h.1M81.3 152h.1M81.6 152.2h.1M81.9 152.4h.1M82.1 152.6h.1M82.4 152.8h.1M82.7 153h.1M83 153.2h.1M83.3 153.4h.1"/>
<path d="M83.6 153.6h.1M83.9 153.8h.1M84.1 154h.1M84.4 154.2h.1M84.7 154.4h.1M84.8 154.4h.1M85.1 154.6h.1M85.3 152.2l2.3 2.4 9.2 5.7 .4 .4h.5M85.4 154.8h.1M85.7 154.9v.1M86 155.1v.1M86.3 155.3h.1"/>
<path d="M86.6 155.5h.1M86.9 155.7h.1M87.2 155.9h.1M87.5 156.1h.1M87.8 156.3h.1M88.2 156.5h.1M88.5 156.7h.1M88.8 156.9h.1M89.1 157.1h.1M89.4 157.3h.1M89.7 157.5h.1M90 157.7h.1"/>
<path d="M90.3 157.9h.1M90.6 158.1h.1M90.9 158.3h.1M91 158.3v.1M91.3 158.5v.1M91.6 158.7h.1M91.9 158.9h.1M92.2 159.1h.1M92.5 159.3h.1M92.8 159.4v.1M93.1 159.6h.1M93.4 159.8h.1"/>
<path d="M93.7 160h.1M95.4 159.9h.1M95.4 159.9l1.5 1.5 2.2-.1M116.2 141.2v9.3l-7 6.9h-8.3l-3.2 3.3M154.9 140l.1 .1M155 140.1h.1M155.2 140.3v.1M155.4 140.6v.1M155.6 140.9h.1M155.9 141.2h.1M156.1 141.4v.1M156.3 141.7h.1"/>
<path d="M156.5 142h.1M156.8 142.2v.1M157 142.5v.1M157.2 142.8h.1M157.4 143.1h.1M157.6 143.3l.1 .1M157.9 143.6v.1M158.1 143.9h.1M158.3 144.2h.1M158.6 144.4v.1M158.8 144.7h.1M159 145h.1"/>
<path d="M159.2 145.2l.1 .1M159.4 145.5l.1 .1M159.7 145.8h.1M159.9 146.1h.1M160.1 146.3v.1M160.3 146.6l.1 .1M160.6 146.9h.1M160.7 159.8h.1M160.8 147.2h.1M160.9 159.5h.1M161 147.4l.1 .1M161.1 159.2h-.1"/>
<path d="M161.2 158.9h.1M161.2 147.7h.1M161.4 158.5v.1M161.5 148h.1M161.6 158.2l-.1 .1M161.7 148.3h.1M161.7 157.9v.1M161.9 157.6v.1M161.9 148.5v.1M162.1 157.3l-.1 .1M162.1 148.8h.1M162.2 157v.1"/>
<path d="M162.4 149.1h.1M162.4 156.7h.1M162.5 156.4h.1M162.6 149.4h.1M162.7 156.1h.1M162.8 149.6v.1M162.9 155.8h.1M163 149.9h.1M163 155.5h.1M163.2 155.2h.1M163.3 150.2h.1M163.4 154.9h.1"/>
<path d="M163.5 150.5h.1M163.5 154.6h.1M163.7 150.7h.1M163.7 154.3h.1M163.9 154h.1M163.9 151h.1M164 153.6v.1M164.2 151.3h.1M164.2 153.4h.1M164.4 153l-.1 .1M164.4 151.5v.1M164.5 152.7v.1"/>
<path d="M164.6 151.8h.1M164.7 152.4v.1M164.8 152.1v.1M94 160.2h.1M94.3 160.3v.1M94.6 160.5h.1M94.9 160.7h.1M95.2 160.9h.1M95.5 161.1h.1M95.8 161.2v.1M96.1 161.4v.1M96.4 161.6l.1 .1"/>
<path d="M96.8 161.8h.1M97.1 161.9h.1M97.4 162.1h.1M97.7 160.7h.1M97.7 162.2h.1M98 161.3v.1M98.1 162.4h.1M98.4 162.5h.1M98.7 162.6l.1 .1M99.1 162.8h.1M99.4 162.9l.1 .1M99.7 163.1h.1"/>
<path d="M100.1 163.2v.1M100.4 163.4h.1M100.7 163.5h.1M101 163.7h.1M101.4 163.8h.1M101.7 164h.1M102 164.1h.1M102.4 164.2v.1M102.7 164.4h.1M103 164.5h.1M103.4 164.7h.1M103.7 164.8h.1"/>
<path d="M104.1 165h.1M104.4 165.1h.1M104.7 165.2h.1M105.1 165.4h.1M105.4 165.5h.1M105.7 165.6h.1M106 165.7l.1 .1M106.4 165.9h.1M106.7 166h.1M107 166.1l.1 .1M107.3 166.3h.1M107.7 166.4h.1"/>
<path d="M108 166.5v.1M108.3 166.7h.1M108.6 166.8h.1M109 166.9h.1M109.3 167.1h.1M109.6 167.2h.1M109.9 167.3h.1M110.3 167.4v.1M110.6 167.6h.1M110.9 167.7h.1M111.3 167.9h.1M111.6 168h.1"/>
<path d="M111.9 168.1h.1M112.2 168.3h.1M112.5 168.4h.1M112.9 168.5h.1M113.2 168.6v.1M113.5 168.8h.1M113.6 167.1l1.2-.4 .6 .2a7.4 7.4 0 0 0 2.8 1.7l.4 .1M113.9 168.9h.1M114.2 169v.1M114.5 169.2h.1M114.8 169.3h.1M115 167.6l3.3 1.4"/>
<path d="M115.2 169.4h.1M115.5 169.6h.1M115.8 169.7h.1M116.1 169.8h.1M116.5 170h.1M116.8 170.1h.1M117.1 170.2h.1M117.4 170.3l.1 .1M117.8 170.5h.1M118.2 170.6h.1M118.3 169l.1 .1M118.4 169.1l1.7 .7 2.9 .8"/>
<path d="M118.5 170.7v.1M118.6 168.7l5.9 1.9h1.3l.3-.3h.9l1.7 1.7 6.3 1h1.9l3.4-.5 5.4-1.5M118.6 168.7h.1M118.8 170.8l.1 .1M119.1 171h.1M119.5 171.1h.1M119.8 171.2h.1M120.1 171.3h.1M120.5 171.4h.1M120.8 171.5h.1M121.1 171.6l.1 .1M121.5 171.8h.1"/>
<path d="M121.8 171.9h.1M122.1 172h.1M122.5 172.1h.1M122.8 172.2h.1M123 170.6l1.4 .4h2.2M123 170.6v.1M123.1 172.3h.1M123.5 172.4v.1M123.8 172.6h.1M124.1 172.7h.1M124.5 172.8h.1M124.8 172.9h.1"/>
<path d="M125.1 173h.1M125.5 173.1h.1M125.8 173.2h.1M126.1 173.4h.1M126.4 173.5h.1M126.8 173.6h.1M127.1 173.7h.1M127.4 173.8h.1M127.8 173.9h.1M128.1 174v.1M128.4 174.2h.1M128.8 174.3h.1"/>
<path d="M129.1 174.4h.1M129.4 174.5h.1M129.8 174.6h.1M130.1 174.7l.1 .1M130.4 174.8l.1 .1M130.8 175h.1M131.1 175.1h.1M131.4 175.2h.1M131.8 175.3h.1M132.1 175.4h.1M132.4 175.5h.1M132.8 175.6v.1"/>
<path d="M133.1 175.7v.1M133.4 175.9h.1M133.8 176h.1M134.1 176.1h.1M134.4 176.2h.1M134.8 176.2h.1M135.1 176.2h.1M135.5 176.1h.1M135.8 176.1h.1M136.2 176.1h.1M136.5 176h.1M136.9 176h.1"/>
<path d="M137.2 176h.1M137.6 175.9h.1M137.9 175.9h.1M138.3 175.9h.1M138.6 175.9h.1M139 175.8h.1M139.3 175.8h.1M139.7 175.7v.1M140 175.7h.1M140.4 175.7h.1M140.7 175.7h.1M141.1 175.6h.1"/>
<path d="M141.4 175.6h.1M141.8 175.6h.1M142.1 175.5h.1M142.5 175.5h.1M142.8 175.5h.1M143.1 175.5h.1M143.5 175.4h.1M143.8 175.4h.1M144.2 175.3v.1M144.5 175.3h.1M144.9 175.3h.1M145.2 175.3h.1"/>
<path d="M145.6 175.2h.1M145.9 175.2h.1M146.3 175.1v.1M146.6 174.9h.1M146.9 174.7h-.1M147.2 174.5h-.1M147.4 174.2v.1M147.7 174h.1M148 173.8h-.1M148.2 173.6h.1M148.5 173.3v.1M148.8 173.1h-.1"/>
<path d="M149 172.9h.1M149.3 172.7h.1M149.6 172.4l-.1 .1M149.8 172.2h.1M150.1 172h.1M150.4 171.8h-.1M150.7 171.5l-.1 .1M150.9 171.3h.1M151.2 171.1h.1M151.5 170.9h-.1M151.7 170.6v.1M152 170.4h.1"/>
<path d="M152.3 170.2h-.1M152.5 170h.1M152.8 169.7v.1M153.1 169.5h.1M153.4 169.3h-.1M153.6 169.1h.1M153.9 168.8v.1M154.2 168.6l-.1 .1M154.4 168.4h.1M154.7 168.2h.1M155 167.9l-.1 .1M155.2 167.7h.1"/>
<path d="M155.5 167.5h.1M155.8 167.3h-.1M156 167v.1M156.3 166.8v.1M156.6 166.6h-.1M156.9 166.4h-.1M157.1 166.1v.1M157.4 165.9h.1M157.6 165.6h.1M157.8 165.3h-.1M157.9 165h.1M158.1 164.7h.1"/>
<path d="M158.2 164.4h.1M158.4 164v.1M158.6 163.7v.1M158.7 163.4v.1M158.9 163.1v.1M159.1 162.8l-.1 .1M159.2 162.5v.1M159.4 162.2h.1M159.6 161.9h.1M159.7 161.6h.1M159.9 161.3h.1M160.1 161h-.1"/>
<path d="M160.2 160.7h.1M160.4 160.4h.1M160.6 160.1h-.1"/>
</g>
<path d="M94.8 115.1l-2.6 2.4h-3.8l-2.6 2.6v4l1 1v3.5M94.8 110.2v4.9M94.8 115.1h.1M116.8 155.1l.2 1v10M119.3 155.1l.4 .3 .2 9 3.5-4.1M139.8 153.9l-11.9 11.9h-5.4l-.7 .3 3.5-4.2" fill="none" stroke="#000" stroke-width=".42"/>
<path d="M93.6 116l.1 2.5" fill="none" stroke="#000" stroke-width=".32"/>
<path d="M66.4 117.5l9.8 8.2M106.7 126.1l9.8 8.3-17.1 10.8 9.8 8.3M139.8 153.9l9.8 8.2" fill="none" stroke="#000" stroke-width="1"/>
<path d="M80.8 105.2l.6 1.4" fill="none" stroke="#000" stroke-width="1.5"/>
<circle cx="81.1" cy="105.9" r=".51" fill="#fff" stroke="#000" stroke-width=".21"/>
<path d="M83 104.1l.7 1.4" fill="none" stroke="#000" stroke-width="1.5"/>
<circle cx="83.4" cy="104.8" r=".51" fill="#fff" stroke="#000" stroke-width=".21"/>
<path d="M85.3 103l.7 1.3" fill="none" stroke="#000" stroke-width="1.5"/>
<circle cx="85.7" cy="103.6" r=".51" fill="#fff" stroke="#000" stroke-width=".21"/>
<circle cx="86.8" cy="128.6" r=".38" fill="#000" stroke="#000" stroke-width=".21"/>
<circle cx="86.8" cy="128.6" r=".17" fill="#fff" stroke="#000" stroke-width=".21"/>
<circle cx="117" cy="166.1" r=".38" fill="#000" stroke="#000" stroke-width=".21"/>
<circle cx="117" cy="166.1" r=".17" fill="#fff" stroke="#000" stroke-width=".21"/>
<circle cx="132" cy="125.8" r=".38" fill="#000" stroke="#000" stroke-width=".21"/>
<circle cx="132" cy="125.8" r=".17" fill="#fff" stroke="#000" stroke-width=".21"/>
<circle cx="99.9" cy="110.2" r=".38" fill="#000" stroke="#000" stroke-width=".21"/>
<circle cx="99.9" cy="110.2" r=".17" fill="#fff" stroke="#000" stroke-width=".21"/>
<circle cx="121.9" cy="111.4" r=".38" fill="#000" stroke="#000" stroke-width=".21"/>
<circle cx="121.9" cy="111.4" r=".17" fill="#fff" stroke="#000" stroke-width=".21"/>
<circle cx="114.9" cy="107.9" r=".38" fill="#000" stroke="#000" stroke-width=".21"/>
<circle cx="114.9" cy="107.9" r=".17" fill="#fff" stroke="#000" stroke-width=".21"/>
<circle cx="107.3" cy="107.2" r=".38" fill="#000" stroke="#000" stroke-width=".21"/>
<circle cx="107.3" cy="107.2" r=".17" fill="#fff" stroke="#000" stroke-width=".21"/>
<circle cx="78.5" cy="124.9" r=".38" fill="#000" stroke="#000" stroke-width=".21"/>
<circle cx="78.5" cy="124.9" r=".17" fill="#fff" stroke="#000" stroke-width=".21"/>
<circle cx="79.2" cy="118" r=".38" fill="#000" stroke="#000" stroke-width=".21"/>
<circle cx="79.2" cy="118" r=".17" fill="#fff" stroke="#000" stroke-width=".21"/>
<circle cx="75.9" cy="112.9" r=".38" fill="#000" stroke="#000" stroke-width=".21"/>
<circle cx="75.9" cy="112.9" r=".17" fill="#fff" stroke="#000" stroke-width=".21"/>
<circle cx="92.4" cy="139.4" r=".38" fill="#000" stroke="#000" stroke-width=".21"/>
<circle cx="92.4" cy="139.4" r=".17" fill="#fff" stroke="#000" stroke-width=".21"/>
<circle cx="131.7" cy="118" r=".38" fill="#000" stroke="#000" stroke-width=".21"/>
<circle cx="131.7" cy="118" r=".17" fill="#fff" stroke="#000" stroke-width=".21"/>
<circle cx="121.6" cy="114.9" r=".38" fill="#000" stroke="#000" stroke-width=".21"/>
<circle cx="121.6" cy="114.9" r=".17" fill="#fff" stroke="#000" stroke-width=".21"/>
<circle cx="111.9" cy="112.4" r=".38" fill="#000" stroke="#000" stroke-width=".21"/>
<circle cx="111.9" cy="112.4" r=".17" fill="#fff" stroke="#000" stroke-width=".21"/>
<circle cx="116.2" cy="141.2" r=".38" fill="#000" stroke="#000" stroke-width=".21"/>
<circle cx="116.2" cy="141.2" r=".17" fill="#fff" stroke="#000" stroke-width=".21"/>
<circle cx="85.3" cy="152.2" r=".38" fill="#000" stroke="#000" stroke-width=".21"/>
<circle cx="85.3" cy="152.2" r=".17" fill="#fff" stroke="#000" stroke-width=".21"/>
<circle cx="65.8" cy="109.3" r=".38" fill="#000" stroke="#000" stroke-width=".21"/>
<circle cx="65.8" cy="109.3" r=".17" fill="#fff" stroke="#000" stroke-width=".21"/>
<circle cx="59.7" cy="117.9" r=".38" fill="#000" stroke="#000" stroke-width=".21"/>
<circle cx="59.7" cy="117.9" r=".17" fill="#fff" stroke="#000" stroke-width=".21"/>
<circle cx="99.3" cy="117.6" r=".38" fill="#000" stroke="#000" stroke-width=".21"/>
<circle cx="99.3" cy="117.6" r=".17" fill="#fff" stroke="#000" stroke-width=".21"/>
<circle cx="92.3" cy="110.3" r=".38" fill="#000" stroke="#000" stroke-width=".21"/>
<circle cx="92.3" cy="110.3" r=".17" fill="#fff" stroke="#000" stroke-width=".21"/>
<circle cx="81.5" cy="114.2" r=".38" fill="#000" stroke="#000" stroke-width=".21"/>
<circle cx="81.5" cy="114.2" r=".17" fill="#fff" stroke="#000" stroke-width=".21"/>
<circle cx="97.7" cy="160.7" r=".38" fill="#000" stroke="#000" stroke-width=".21"/>
<circle cx="97.7" cy="160.7" r=".17" fill="#fff" stroke="#000" stroke-width=".21"/>
<circle cx="124.5" cy="136.8" r=".38" fill="#000" stroke="#000" stroke-width=".21"/>
<circle cx="124.5" cy="136.8" r=".17" fill="#fff" stroke="#000" stroke-width=".21"/>
<circle cx="127.2" cy="129.6" r=".38" fill="#000" stroke="#000" stroke-width=".21"/>
<circle cx="127.2" cy="129.6" r=".17" fill="#fff" stroke="#000" stroke-width=".21"/>
<circle cx="145.8" cy="171" r=".38" fill="#000" stroke="#000" stroke-width=".21"/>
<circle cx="145.8" cy="171" r=".17" fill="#fff" stroke="#000" stroke-width=".21"/>
<circle cx="128.1" cy="171.4" r=".38" fill="#000" stroke="#000" stroke-width=".21"/>
<circle cx="128.1" cy="171.4" r=".17" fill="#fff" stroke="#000" stroke-width=".21"/>
<circle cx="113.6" cy="167.1" r=".38" fill="#000" stroke="#000" stroke-width=".21"/>
<circle cx="113.6" cy="167.1" r=".17" fill="#fff" stroke="#000" stroke-width=".21"/>
<circle cx="126.6" cy="122.3" r=".38" fill="#000" stroke="#000" stroke-width=".21"/>
<circle cx="126.6" cy="122.3" r=".17" fill="#fff" stroke="#000" stroke-width=".21"/>
<circle cx="114.7" cy="141.3" r=".38" fill="#000" stroke="#000" stroke-width=".21"/>
<circle cx="114.7" cy="141.3" r=".17" fill="#fff" stroke="#000" stroke-width=".21"/>
<circle cx="112.9" cy="100.3" r=".38" fill="#000" stroke="#000" stroke-width=".21"/>
<circle cx="112.9" cy="100.3" r=".17" fill="#fff" stroke="#000" stroke-width=".21"/>
<circle cx="119.5" cy="109.1" r=".38" fill="#000" stroke="#000" stroke-width=".21"/>
<circle cx="119.5" cy="109.1" r=".17" fill="#fff" stroke="#000" stroke-width=".21"/>
<circle cx="105.4" cy="114.8" r=".38" fill="#000" stroke="#000" stroke-width=".21"/>
<circle cx="105.4" cy="114.8" r=".17" fill="#fff" stroke="#000" stroke-width=".21"/>
<circle cx="131.7" cy="110.8" r=".38" fill="#000" stroke="#000" stroke-width=".21"/>
<circle cx="131.7" cy="110.8" r=".17" fill="#fff" stroke="#000" stroke-width=".21"/>
<circle cx="100.5" cy="122.7" r=".38" fill="#000" stroke="#000" stroke-width=".21"/>
<circle cx="100.5" cy="122.7" r=".17" fill="#fff" stroke="#000" stroke-width=".21"/>
<circle cx="136" cy="122" r=".38" fill="#000" stroke="#000" stroke-width=".21"/>
<circle cx="136" cy="122" r=".17" fill="#fff" stroke="#000" stroke-width=".21"/>
<circle cx="150.8" cy="148.1" r=".38" fill="#000" stroke="#000" stroke-width=".21"/>
<circle cx="150.8" cy="148.1" r=".17" fill="#fff" stroke="#000" stroke-width=".21"/>
<circle cx="120.4" cy="114.1" r=".38" fill="#000" stroke="#000" stroke-width=".21"/>
<circle cx="120.4" cy="114.1" r=".17" fill="#fff" stroke="#000" stroke-width=".21"/>
<circle cx="72.9" cy="141.6" r=".38" fill="#000" stroke="#000" stroke-width=".21"/>
<circle cx="72.9" cy="141.6" r=".17" fill="#fff" stroke="#000" stroke-width=".21"/>
<circle cx="63.9" cy="131.1" r=".38" fill="#000" stroke="#000" stroke-width=".21"/>
<circle cx="63.9" cy="131.1" r=".17" fill="#fff" stroke="#000" stroke-width=".21"/>
<circle cx="135.8" cy="119.5" r=".38" fill="#000" stroke="#000" stroke-width=".21"/>
<circle cx="135.8" cy="119.5" r=".17" fill="#fff" stroke="#000" stroke-width=".21"/>
<circle cx="120.8" cy="109.8" r=".38" fill="#000" stroke="#000" stroke-width=".21"/>
<circle cx="120.8" cy="109.8" r=".17" fill="#fff" stroke="#000" stroke-width=".21"/>
<circle cx="111.4" cy="100.3" r=".38" fill="#000" stroke="#000" stroke-width=".21"/>
<circle cx="111.4" cy="100.3" r=".17" fill="#fff" stroke="#000" stroke-width=".21"/>
<circle cx="102.3" cy="101.6" r=".38" fill="#000" stroke="#000" stroke-width=".21"/>
<circle cx="102.3" cy="101.6" r=".17" fill="#fff" stroke="#000" stroke-width=".21"/>
<circle cx="96.7" cy="114.7" r=".38" fill="#000" stroke="#000" stroke-width=".21"/>
<circle cx="96.7" cy="114.7" r=".17" fill="#fff" stroke="#000" stroke-width=".21"/>
<circle cx="142.8" cy="140.7" r=".38" fill="#000" stroke="#000" stroke-width=".21"/>
<circle cx="142.8" cy="140.7" r=".17" fill="#fff" stroke="#000" stroke-width=".21"/>
<circle cx="101.5" cy="112.8" r=".38" fill="#000" stroke="#000" stroke-width=".21"/>
<circle cx="101.5" cy="112.8" r=".17" fill="#fff" stroke="#000" stroke-width=".21"/>
<circle cx="135.8" cy="120.5" r=".38" fill="#000" stroke="#000" stroke-width=".21"/>
<circle cx="135.8" cy="120.5" r=".17" fill="#fff" stroke="#000" stroke-width=".21"/>
<circle cx="104.4" cy="115.9" r=".38" fill="#000" stroke="#000" stroke-width=".21"/>
<circle cx="104.4" cy="115.9" r=".17" fill="#fff" stroke="#000" stroke-width=".21"/>
<circle cx="92.6" cy="106.3" r=".38" fill="#000" stroke="#000" stroke-width=".21"/>
<circle cx="92.6" cy="106.3" r=".17" fill="#fff" stroke="#000" stroke-width=".21"/>
<circle cx="79.5" cy="112.3" r=".38" fill="#000" stroke="#000" stroke-width=".21"/>
<circle cx="79.5" cy="112.3" r=".17" fill="#fff" stroke="#000" stroke-width=".21"/>
<circle cx="100.8" cy="102.1" r=".38" fill="#000" stroke="#000" stroke-width=".21"/>
<circle cx="100.8" cy="102.1" r=".17" fill="#fff" stroke="#000" stroke-width=".21"/>
<circle cx="67.3" cy="109.2" r=".38" fill="#000" stroke="#000" stroke-width=".21"/>
<circle cx="67.3" cy="109.2" r=".17" fill="#fff" stroke="#000" stroke-width=".21"/>
<circle cx="59.8" cy="119.4" r=".38" fill="#000" stroke="#000" stroke-width=".21"/>
<circle cx="59.8" cy="119.4" r=".17" fill="#fff" stroke="#000" stroke-width=".21"/>
<circle cx="93.8" cy="125.7" r=".38" fill="#000" stroke="#000" stroke-width=".21"/>
<circle cx="93.8" cy="125.7" r=".17" fill="#fff" stroke="#000" stroke-width=".21"/>
<circle cx="126.6" cy="171" r=".38" fill="#000" stroke="#000" stroke-width=".21"/>
<circle cx="126.6" cy="171" r=".17" fill="#fff" stroke="#000" stroke-width=".21"/>
<circle cx="115" cy="167.6" r=".38" fill="#000" stroke="#000" stroke-width=".21"/>
<circle cx="115" cy="167.6" r=".17" fill="#fff" stroke="#000" stroke-width=".21"/>
<circle cx="155.2" cy="162.9" r=".38" fill="#000" stroke="#000" stroke-width=".21"/>
<circle cx="155.2" cy="162.9" r=".17" fill="#fff" stroke="#000" stroke-width=".21"/>
<circle cx="135.3" cy="132" r=".38" fill="#000" stroke="#000" stroke-width=".21"/>
<circle cx="135.3" cy="132" r=".17" fill="#fff" stroke="#000" stroke-width=".21"/>
<circle cx="99.1" cy="161.3" r=".38" fill="#000" stroke="#000" stroke-width=".21"/>
<circle cx="99.1" cy="161.3" r=".17" fill="#fff" stroke="#000" stroke-width=".21"/>
<circle cx="84.1" cy="151.4" r=".38" fill="#000" stroke="#000" stroke-width=".21"/>
<circle cx="84.1" cy="151.4" r=".17" fill="#fff" stroke="#000" stroke-width=".21"/>
<circle cx="63.1" cy="129.9" r=".38" fill="#000" stroke="#000" stroke-width=".21"/>
<circle cx="63.1" cy="129.9" r=".17" fill="#fff" stroke="#000" stroke-width=".21"/>
<circle cx="74.1" cy="142.5" r=".38" fill="#000" stroke="#000" stroke-width=".21"/>
<circle cx="74.1" cy="142.5" r=".17" fill="#fff" stroke="#000" stroke-width=".21"/>
<circle cx="81" cy="112.4" r=".38" fill="#000" stroke="#000" stroke-width=".21"/>
<circle cx="81" cy="112.4" r=".17" fill="#fff" stroke="#000" stroke-width=".21"/>
<circle cx="91.4" cy="107.1" r=".38" fill="#000" stroke="#000" stroke-width=".21"/>
<circle cx="91.4" cy="107.1" r=".17" fill="#fff" stroke="#000" stroke-width=".21"/>
<circle cx="79.6" cy="113.3" r=".38" fill="#000" stroke="#000" stroke-width=".21"/>
<circle cx="79.6" cy="113.3" r=".17" fill="#fff" stroke="#000" stroke-width=".21"/>
<circle cx="126.5" cy="133.9" r=".38" fill="#000" stroke="#000" stroke-width=".21"/>
<circle cx="126.5" cy="133.9" r=".17" fill="#fff" stroke="#000" stroke-width=".21"/>
<circle cx="135.3" cy="134.9" r=".38" fill="#000" stroke="#000" stroke-width=".21"/>
<circle cx="135.3" cy="134.9" r=".17" fill="#fff" stroke="#000" stroke-width=".21"/>
<circle cx="91.1" cy="118.4" r=".38" fill="#000" stroke="#000" stroke-width=".21"/>
<circle cx="91.1" cy="118.4" r=".17" fill="#fff" stroke="#000" stroke-width=".21"/>
<circle cx="90.2" cy="118.5" r=".38" fill="#000" stroke="#000" stroke-width=".21"/>
<circle cx="90.2" cy="118.5" r=".17" fill="#fff" stroke="#000" stroke-width=".21"/>
<circle cx="89.2" cy="118.5" r=".38" fill="#000" stroke="#000" stroke-width=".21"/>
<circle cx="89.2" cy="118.5" r=".17" fill="#fff" stroke="#000" stroke-width=".21"/>
<circle cx="88" cy="115" r=".38" fill="#000" stroke="#000" stroke-width=".21"/>
<circle cx="88" cy="115" r=".17" fill="#fff" stroke="#000" stroke-width=".21"/>
<g fill="none" stroke="#000" stroke-width=".21">
<path d="M59.9 110.7a9.1 9.1 0 0 1 8.1-3.1l1.9 .1 2.7 .5 3.6 1.7 2.5 .7 2 .1 3.5-.5-.3-1.5-3.6-.1-2.3-4.2 8.1-3.9 2.5 4-1.1 .9 1.3 1.7a49.6 49.6 0 0 1 12-6.8l3.8-1 5.3-.5a16.4 16.4 0 0 1 10 1.5 27.1 27.1 0 0 1 13.6 10.1l2.2 4.2 1.4 3.5 .3 2.8a42.2 42.2 0 0 0 3 13.4 24.9 24.9 0 0 0 9 10l2.9 3 2.3 3.2 1.6 3.1a23.6 23.6 0 0 1 .9 8.6 14.7 14.7 0 0 1-6.8 8.2l-1.8 1.2-1.8 .8-2.8 .8-6.6 1h-2.4a85 85 0 0 1-15-3.2 21.8 21.8 0 0 0-6.2-2.1 3 3 0 0 0-1.5 2.9 20.9 20.9 0 0 0 .6 8.5l2.1 4.6a5.4 5.4 0 0 1-1.6 6.8 7.1 7.1 0 0 1-4.3 1.7 4.6 4.6 0 0 0-3.7 2 5.1 5.1 0 0 1-4.7 2.3 9.5 9.5 0 0 1-7.8-1.1 15.8 15.8 0 0 1-5-4.1l-3.6-3.4-1.6-.4-1.3-1.2a13.2 13.2 0 0 1-1.1-9.7 23 23 0 0 1 2.4-7.1 45.6 45.6 0 0 0 3.3-15.4l-.5-.4a88.9 88.9 0 0 1-15.4-14.1l-6.7-7.7-1.9-2.9-2.5-5.4a37 37 0 0 1-.8-10l.4-1.8 .6-1.4zM73 112.7l39.9 33.4-10.3 12.2-39.8-33.4zM84.1 116.9l1.3 1.1M84.3 115.1h.4l4.2 3.6v.3l-2 2.4-.3-.1-4.2-3.6v-.2zM84.9 118.2h1.5M85 116.7l2.3 1.9-1 1.2-2.3-2zM85.3 118.6l1.1 .3 .8 .6M85.6 117.5v1.5M88 115.5l.7 .6M88.1 113.8l2.3 1.9-1.3 1.5-2.3-1.9zM88.1 115.5h.9M88.5 115l.7 .5"/>
<path d="M88.6 115.1v.9M92.7 113.7h1.9v2.9h-1.9zM92.7 118.6h3v3h-3zM93.2 114.8v.7M93.3 115.2h.7M93.6 114.9v.6M94.1 114.8v.7M94.2 119.5v1.2M94.5 108.7h5.6v3.1h-5.6zM96.8 110.2h1.1M97.3 109.7v1.1M97.6 115.5h3v1.9h-3z"/>
<path d="M97.6 117.5h3v2h-3zM97.6 119.7h3v1.9h-3zM98.7 116.8h.8M98.7 116.1h.8M98.7 118.8h.8M98.7 118.1h.8M98.8 116.5h.6M98.8 118.5h.6M99.1 116.2v.5M99.1 118.2v.5M117.6 102.2a4.8 4.8 0 0 1 3.7 .3l3.5 1.8 2.4 1.5 .5 .6 .5 1.4-1 1.9-10.6-5.8zM86.8 135.5h2"/>
<path d="M87.8 134.5v2M92.8 123.4h2v2.9h-2zM93.4 124.4v.9M93.5 124.8h.6M93.6 120.1h1.2M93.8 124.5v.6M94.1 124.4v.9M97.6 121.7h3v2h-3zM97.6 123.7h3v2h-3zM98.7 121h.8M98.7 120.3h.8M98.7 123h.8"/>
<path d="M98.7 122.3h.8M98.7 125.1h.8M98.7 124.4h.8M98.8 120.6h.6M98.8 122.7h.6M98.8 124.7h.6M99.1 120.4v.5M99.1 122.4v.5M99.1 124.4v.5M113.4 121.3l39.8 33.4-10.3 12.3-39.8-33.5zM117.2 154.6h1.7v1.1h-1.7zM117.7 155.1h.7"/>
<path d="M118 154.8v.7M121.4 159.6l6.9 5.7-2.6 3.1-6.9-5.8zM127.2 144.1h2M128.2 143.1v2M122.5 164h2.1M123.5 163v2"/>
<circle cx="96.3" cy="122.1" r=".23"/>
</g>
<path d="M125.6 155.4l2.1 1.8M125.6 155.4l1.3 .2-1.1 1.1zM129.9 158.7l2.1 1.8M130.7 160.4l1.1-1.1 .2 1.2z" fill="none" stroke="#000" stroke-width=".42"/>
<g fill="#000" stroke="#000" stroke-width=".21">
<path d="M88.2 114.6l.3 .3-.5 .7-.3-.3zM89.2 115.5l.3 .2-.5 .7-.4-.3zM93.2 115.5h.9v.5h-.9zM93.2 114.3h.9v.6h-.9zM94.3 109.1h.2v2.2h-.2zM94.9 108.7h.5v3.1h-.5zM98.3 116h.4v.9h-.4zM98.3 118.1h.4v.8h-.4zM99.5 116h.4v.9h-.4zM99.5 118.1h.4v.8h-.4zM100.2 109.1h.1v2.2h-.1zM93.3 125.2h.9v.5h-.9z"/>
<path d="M93.3 124h.9v.4h-.9zM98.3 120.2h.4v.9h-.4zM98.3 122.2h.4v.9h-.4zM98.3 124.3h.4v.8h-.4zM99.5 120.2h.4v.9h-.4zM99.5 122.2h.4v.9h-.4zM99.5 124.3h.4v.8h-.4zM116.7 155h.5v.3h-.5zM117.4 154.6h.6v1.1h-.6zM117.2 154.6h.8v1.1h-.8zM118.9 155h.5v.3h-.5z"/>
</g>
<g fill="none" stroke="#000" stroke-width=".25">
<path d="M84 119.6l-.1-.2h-.3l.1 .6a.28 .28 0 0 1-.3 .3 .28 .28 0 0 1-.3-.4M88.8 113.4l.5 .3 .2-.3-.3-.4-.7 .8M89.1 113.6l-.1 .5M90 113.8v-.1l.5 .4-.9 .6M91.3 115.2v.4l.2 .1h.7l.1-.5M92.3 114.2v.5M92.3 114.4h-1l.2 .3M99.1 112.2h-.3l-.1 .2v.7l.4 .1M99.6 112.4a.28 .28 0 0 1 .4-.2 .28 .28 0 0 1 .1 .4l-.5 .6h.6M100.7 118.6l.5-.1v-.3l-.5-.1v1M100.8 116.6l.5-.1 .1-.2-.2-.2h-.4v1M101.1 118.6l.2 .5"/>
<path d="M101.2 116.6l.2 .5M101.9 118.3a.28 .28 0 0 1 .4-.2 .28 .28 0 0 1 0 .4l-.4 .6h.5M102 116.3l.2-.2v1M102 117.1h.5M77.1 132.4l.4 .6 .6 .2M77.4 129.3l.7 .7-1.1-.2 .8 .6M77.9 131.7l-.3 .3 .8 .7M78.1 128.5l-.3 .3 .8 .7 .3-.4M78.2 131.3l.6 .6 .3-.1M78.2 132l-.3 .3M78.4 128.8l-.3 .3M78.8 127.6l-.3 .5 .8 .5 .3-.3-.5-.4-.1 .2"/>
<path d="M79.2 130.1l.7 .5h.3M79.3 130.9l-.2 .3 .3 .2 .2-.2-.4-.3-.1-.1-.2 .2M79.7 130.1l-.3 .3M80.1 127l-.4 .6M80.5 128.7l-.3 .2 .1 .3 .5-.1a.28 .28 0 0 1 .3 .3 .28 .28 0 0 1-.3 .2M80.7 128.3h.1M81 128.5l.5 .4M81.4 127.6l.7 .6-.2 .3-.5-.4 .2-.3M82.3 126.3l.6 .2 .3 .6M82.8 127.4l-.3 .3-.1-.1-.3-.2 .1-.3 .3 .1-.2 .3M84.1 133.1l.9-.6-.4 1M84.3 132.9l.5 .4"/>
<path d="M84.4 120.1a.28 .28 0 0 1 .4 .1 .28 .28 0 0 1-.2 .4l-.7 .1 .4 .4M85 133.8l.9-.6-.4 1M85.2 133.7l.4 .3M86.8 134.6l.2 .2M87.1 134.2l.3 .4-.2 .2h-.2l.1 .2-.3 .3-.4-.3zM87.7 135.2l.2 .4-.3 .4-.3-.3 .1-.2 .4 .2M88.4 135.8l.2 .2M88.7 135.6l-.6 .6 .1 .3M88.9 136.2l.3 .2M89.2 136l-.5 .7 .1 .3M89.4 137l.3 .3 .1-.3-.3-.1-.2 .2-.1 .2 .3 .3M90.6 137.7l-.2-.3-.5 .5"/>
<path d="M90.8 125l.5-.1v-.4l-.5-.1v1M90.9 137.9l-.2 .7M91.1 125l.3 .4M91.3 138.2l-1 .5M91.9 124.8h.3a.29 .29 0 0 1 .3 .4 .29 .29 0 0 1-.3 .2 .29 .29 0 0 1-.3-.3zM92.4 124.4l-.3 .1-.2 .3M95.9 129.1h1M95.9 127.2v.2M95.9 127.8v.6M95.9 128.8v.6M95.9 128.1h1M95.9 127.3h1"/>
<path d="M95.9 126h1l-1 .6h1M95.9 124.8l.5 .4M96 122.7a.56 .56 0 0 1 .9 .3 .5 .5 0 0 1-.6 .2 .5 .5 0 0 1-.3-.5zM96.1 122.6l.6 .5M96.4 125.2l-.5 .3M96.4 125.2h.5M96.7 129.9v.5M96.9 123.7v.6l-.5-.5a.28 .28 0 0 0-.5 .1 .28 .28 0 0 0 .2 .4M96.9 129.8l-1 .4 1 .3M96.9 127.2v.2M98.3 139.1l.6 .2 .3 .6M100.7 120.7l.5-.1v-.4l-.5-.1v1.1"/>
<path d="M100.8 124.8l.5-.1v-.3l-.5-.2v1.1M101 122.7l.5-.1v-.3l-.5-.1v1M101.1 120.7l.2 .5M101.1 124.8l.2 .5M101.3 122.7l.2 .5M101.9 120.1l.4 .1 .1 .2-.1 .1-.3 .1M102.2 120.6l.2 .2v.3l-.5 .1M102.3 122.2l-.2 .8h.6M102.5 124.2h-.6v.5h.5l.1 .2-.1 .3-.5 .1M102.5 122.7v.5M117.8 138l.7 .6-1.1-.2 .8 .6M118.4 137.1l-.2 .4 .8 .6 .2-.3"/>
<path d="M118.6 140l.6 .5h.2M118.7 137.5l-.2 .3M119.2 136.3l-.3 .4 .5 .5h.2l.4-.3-.5-.4-.1 .2M119.6 138.7l.6 .6 .3-.1M119.7 139.6l-.2 .3 .3 .2 .2-.3-.4-.3-.2-.1-.2 .3M120 138.7l-.2 .3M120.5 135.7l-.4 .5M120.8 137.4l-.2 .3 .2 .2 .4-.2a.28 .28 0 0 1 .3 .3 .28 .28 0 0 1-.4 .3M121.1 136.9h.1M121.4 137.1l.5 .4M121.7 136.2l.8 .6-.2 .3-.5-.3 .2-.4M122.6 134.9l.7 .2 .3 .6"/>
<path d="M123.2 136l-.5 .3-.2-.3 .1-.3 .3 .1-.3 .4M92.5 145.9l.4 .6 .6 .2M93 145.6l.7 .6M93.2 143.3l.2-.5-.2-.2-.4 .3 .7 .6M93.3 145.1l.8 .7M93.6 141.8h.4l.4 .4v.3l-.2 .1-.2-.1-.4-.4zM93.7 145.4l-.4 .5M94.5 144.7l-.2 .4 .2 .1 .3-.2-.4-.3-.4 .2M94.5 140.9l-.2 .1v.4l.6-.2a.28 .28 0 0 1 .3 .4 .28 .28 0 0 1-.4 .2M94.9 143.8l-.2 .4 .6-.1 .1 .1-.3 .3M95.3 140.3l.5 .4M95.7 142.4h.3v.3l.4-.1 .1 .3-.3 .4-.7-.7z"/>
<path d="M95.8 140.2l-.5 .6M96 142.7l-.2 .2M96.7 141.6l.5 .5-.3 .2-.5-.3M97.4 140.9l.5 .4M98.1 141.1l-.6-.4-.4 .4 .6 .5M98.5 140.5l.2-.3-.4-.4-.3 .3 .8 .7M117.3 151.7l.5 .2 .1 .6-.2 .2h-.4zM117.5 141l.3 .6 .7 .2M118.2 140.3l-.2 .4 .7 .6M118.5 152.7h.5M118.5 152l.3-.3v1M118.6 140.6l-.3 .3"/>
<path d="M124.5 141.7l.9-.6-.4 1M124.7 141.6l.4 .3M125.4 142.4l.9-.5-.4 1M125.6 157.8l.3-.1 .1 .3-.3 .5-.3 .1-.2-.3zM125.6 142.3l.4 .3M127.1 158.7l-.7 .8 .2-1.2-.6 .8M127.2 143.2l.2 .2M127.5 142.9l.3 .4-.2 .1h-.2l.1 .3-.4 .2-.3-.3zM127.9 159.3l-1.1 .6M128.1 159.9l.2-.1 .3 .2-.4 .6-.3 .1-.2-.3zM128.1 143.8l.2 .4-.3 .4-.3-.2 .1-.3 .4 .2M128.8 144.4l.2 .2"/>
<path d="M129.1 144.2l-.6 .6 .1 .3M129.3 144.9l.3 .2M129.6 144.7l-.5 .6v.3M129.7 145.6l.4 .3 .1-.3-.3-.1-.3 .3 .3 .4M130.9 146.4l-.2-.3-.4 .5M131.3 146.5l-.3 .7M131.6 146.8l-1 .5M132.9 154.6l.3 .5 .7 .3M133.3 154.2l.8 .7M133.5 151.9l.3-.5-.3-.2-.4 .3 .8 .7M133.7 153.8l.8 .6M134 150.5l.3-.1 .4 .3v.5h-.3l-.4-.3z"/>
<path d="M134 154.1l-.3 .4M134.9 153.4l-.3 .3 .1 .2h.2l.2-.3-.3-.3h-.2l-.2 .2M134.9 149.5l-.3 .3 .1 .2 .7-.1 .2 .1-.1 .2-.3 .2M135.3 152.5l-.2 .2 .1 .2 .5-.1-.2 .3M135.7 148.9l.5 .5M136 151h.3l.1 .3h.4l.1 .2-.3 .4-.8-.7zM136.1 148.9l-.4 .5M136.4 151.3l-.2 .2M137.1 150.3l.5 .4-.2 .2-.1 .1-.5-.4M137.7 149.5l.5 .4M138.5 149.7l-.4-.3h-.3l-.3 .4 .5 .4M138.6 147.7l.7 .3 .3 .5"/>
<path d="M138.9 149.2l.2-.4-.5-.3-.2 .2 .7 .7M128.9 160.8l.3 .3M129.5 160.7l-.3-.3-.7 .8M129.6 161.4l.4 .3M130.3 161.4l-.4-.3-.6 .7"/>
</g>
<use href="#words"/>
</svg>
